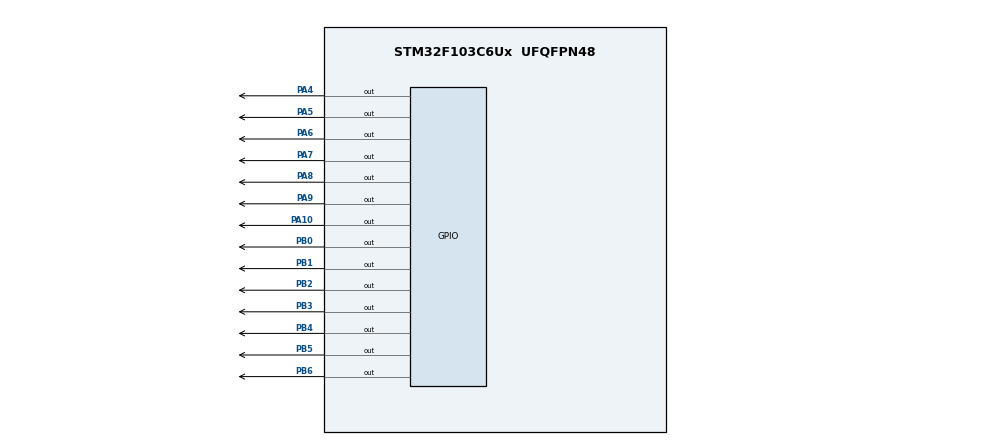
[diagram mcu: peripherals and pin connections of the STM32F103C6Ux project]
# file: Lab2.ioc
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Mcu.Family=STM32F1
Mcu.Name=STM32F103C6Ux
Mcu.Package=UFQFPN48
NVIC.PriorityGroup=NVIC_PRIORITYGROUP_4
NVIC.TIM2_IRQn=true\:0\:0\:false\:false\:true\:true\:true
PA10.Signal=GPIO_Output
PA4.Signal=GPIO_Output
PA5.Signal=GPIO_Output
PA6.Signal=GPIO_Output
PA7.Signal=GPIO_Output
PA8.Signal=GPIO_Output
PA9.Signal=GPIO_Output
PB0.Signal=GPIO_Output
PB1.Signal=GPIO_Output
PB2.Signal=GPIO_Output
PB3.Signal=GPIO_Output
PB4.Signal=GPIO_Output
PB5.Signal=GPIO_Output
PB6.Signal=GPIO_Output
ProjectManager.HeapSize=0x200
ProjectManager.StackSize=0x400
ProjectManager.TargetToolchain=STM32CubeIDE
RCC.APB1Freq_Value=8000000
RCC.APB2Freq_Value=8000000
TIM2.Period=9
TIM2.Prescaler=7999
VP_SYS_VS_ND.Mode=No_Debug
VP_TIM2_VS_ClockSourceINT.Mode=Internal
board=custom

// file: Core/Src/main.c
/* USER CODE BEGIN Header */
/**
  ******************************************************************************
  * @file           : main.c
  * @brief          : Main program body
  ******************************************************************************
  * @attention
  *
  * <h2><center>&copy; Copyright (c) 2021 STMicroelectronics.
  * All rights reserved.</center></h2>
  *
  * This software component is licensed by ST under BSD 3-Clause license,
  * the "License"; You may not use this file except in compliance with the
  * License. You may obtain a copy of the License at:
  *                        opensource.org/licenses/BSD-3-Clause
  *
  ******************************************************************************
  */
/* USER CODE END Header */
#include "main.h"

TIM_HandleTypeDef htim2;

void SystemClock_Config(void);
static void MX_TIM2_Init(void);
static void MX_GPIO_Init(void);

/* USER CODE BEGIN 0 */
int counter = 0;
int sw = 0;
const int MAX_LED = 4;
int index_led = 0;
int led_buffer [4] = {1 , 2 , 3 , 4};
int hour = 15 , minute = 8 , second = 50;

void update7SEG ( int index ) {
	switch ( index ) {
	case 0:
		HAL_GPIO_WritePin ( GPIOA , GPIO_PIN_7, SET ) ;
		HAL_GPIO_WritePin ( GPIOA , GPIO_PIN_8, SET ) ;
		HAL_GPIO_WritePin ( GPIOA , GPIO_PIN_9, SET ) ;
		display7SEG (led_buffer[index]);
		HAL_GPIO_WritePin ( GPIOA , GPIO_PIN_6, RESET ) ;
		break;
	case 1:
		HAL_GPIO_WritePin ( GPIOA , GPIO_PIN_6, SET ) ;
		HAL_GPIO_WritePin ( GPIOA , GPIO_PIN_8, SET ) ;
		HAL_GPIO_WritePin ( GPIOA , GPIO_PIN_9, SET ) ;
		display7SEG (led_buffer[index]);
		HAL_GPIO_WritePin ( GPIOA , GPIO_PIN_7, RESET ) ;
		break;
	case 2:
		HAL_GPIO_WritePin ( GPIOA , GPIO_PIN_6, SET ) ;
		HAL_GPIO_WritePin ( GPIOA , GPIO_PIN_7, SET ) ;
		HAL_GPIO_WritePin ( GPIOA , GPIO_PIN_9, SET ) ;
		display7SEG (led_buffer[index]);
		HAL_GPIO_WritePin ( GPIOA , GPIO_PIN_8, RESET ) ;
		break;
	case 3:
		HAL_GPIO_WritePin ( GPIOA , GPIO_PIN_6, SET ) ;
		HAL_GPIO_WritePin ( GPIOA , GPIO_PIN_7, SET ) ;
		HAL_GPIO_WritePin ( GPIOA , GPIO_PIN_8, SET ) ;
		display7SEG (led_buffer[index]);
		HAL_GPIO_WritePin ( GPIOA , GPIO_PIN_9, RESET ) ;
		break;
	default:
		break;
	}
}

void updateClockBuffer(){
	led_buffer[0] = hour/10;
	led_buffer[1] = hour%10;
	led_buffer[2] = minute/10;
	led_buffer[3] = minute%10;
}
uint8_t data[8] = {0xf7, 0xeb, 0xdd, 0xc1, 0xdd, 0xdd, 0xdd,0xff};
const int MAX_LED_MATRIX = 8;
int index_led_matrix = 0;
uint8_t matrix_buffer[8] = {0x01 , 0x02 , 0x03 , 0x04 , 0x05 , 0x06 , 0x07 , 0x08 };
void updateLEDMatrix (int index ) {
	switch ( index ) {
		case 0:
			HAL_GPIO_WritePin ( GPIOB , GPIO_PIN_8, SET ) ;
			HAL_GPIO_WritePin ( GPIOB , GPIO_PIN_9, SET ) ;
			HAL_GPIO_WritePin ( GPIOB , GPIO_PIN_10, SET ) ;
			HAL_GPIO_WritePin ( GPIOB , GPIO_PIN_11, SET ) ;
			HAL_GPIO_WritePin ( GPIOB , GPIO_PIN_12, SET ) ;
			HAL_GPIO_WritePin ( GPIOB , GPIO_PIN_13, SET ) ;
			HAL_GPIO_WritePin ( GPIOB , GPIO_PIN_14, SET ) ;
			HAL_GPIO_WritePin ( GPIOB , GPIO_PIN_15, SET ) ;
			displayMatrix(data[index]);
			data[index]=displayChange(data[index]);
			HAL_GPIO_WritePin ( GPIOB , GPIO_PIN_8, RESET ) ;
			break;
		case 1:
			HAL_GPIO_WritePin ( GPIOB , GPIO_PIN_8, SET ) ;
			HAL_GPIO_WritePin ( GPIOB , GPIO_PIN_9, SET ) ;
			HAL_GPIO_WritePin ( GPIOB , GPIO_PIN_10, SET ) ;
			HAL_GPIO_WritePin ( GPIOB , GPIO_PIN_11, SET ) ;
			HAL_GPIO_WritePin ( GPIOB , GPIO_PIN_12, SET ) ;
			HAL_GPIO_WritePin ( GPIOB , GPIO_PIN_13, SET ) ;
			HAL_GPIO_WritePin ( GPIOB , GPIO_PIN_14, SET ) ;
			HAL_GPIO_WritePin ( GPIOB , GPIO_PIN_15, SET ) ;
			displayMatrix(data[index]);
			data[index]=displayChange(data[index]);
			HAL_GPIO_WritePin ( GPIOB , GPIO_PIN_9, RESET ) ;
			break;
		case 2:
			HAL_GPIO_WritePin ( GPIOB , GPIO_PIN_8, SET ) ;
			HAL_GPIO_WritePin ( GPIOB , GPIO_PIN_9, SET ) ;
			HAL_GPIO_WritePin ( GPIOB , GPIO_PIN_10, SET ) ;
			HAL_GPIO_WritePin ( GPIOB , GPIO_PIN_11, SET ) ;
			HAL_GPIO_WritePin ( GPIOB , GPIO_PIN_12, SET ) ;
			HAL_GPIO_WritePin ( GPIOB , GPIO_PIN_13, SET ) ;
			HAL_GPIO_WritePin ( GPIOB , GPIO_PIN_14, SET ) ;
			HAL_GPIO_WritePin ( GPIOB , GPIO_PIN_15, SET ) ;
			displayMatrix(data[index]);
			data[index]=displayChange(data[index]);
			HAL_GPIO_WritePin ( GPIOB , GPIO_PIN_10, RESET ) ;
			break;
		case 3:
			HAL_GPIO_WritePin ( GPIOB , GPIO_PIN_8, SET ) ;
			HAL_GPIO_WritePin ( GPIOB , GPIO_PIN_9, SET ) ;
			HAL_GPIO_WritePin ( GPIOB , GPIO_PIN_10, SET ) ;
			HAL_GPIO_WritePin ( GPIOB , GPIO_PIN_11, SET ) ;
			HAL_GPIO_WritePin ( GPIOB , GPIO_PIN_12, SET ) ;
			HAL_GPIO_WritePin ( GPIOB , GPIO_PIN_13, SET ) ;
			HAL_GPIO_WritePin ( GPIOB , GPIO_PIN_14, SET ) ;
			HAL_GPIO_WritePin ( GPIOB , GPIO_PIN_15, SET ) ;
			displayMatrix(data[index]);
			data[index]=displayChange(data[index]);
			HAL_GPIO_WritePin ( GPIOB , GPIO_PIN_11, RESET ) ;
			break;
		case 4:
			HAL_GPIO_WritePin ( GPIOB , GPIO_PIN_8, SET ) ;
			HAL_GPIO_WritePin ( GPIOB , GPIO_PIN_9, SET ) ;
			HAL_GPIO_WritePin ( GPIOB , GPIO_PIN_10, SET ) ;
			HAL_GPIO_WritePin ( GPIOB , GPIO_PIN_11, SET ) ;
			HAL_GPIO_WritePin ( GPIOB , GPIO_PIN_12, SET ) ;
			HAL_GPIO_WritePin ( GPIOB , GPIO_PIN_13, SET ) ;
			HAL_GPIO_WritePin ( GPIOB , GPIO_PIN_14, SET ) ;
			HAL_GPIO_WritePin ( GPIOB , GPIO_PIN_15, SET ) ;
			displayMatrix(data[index]);
			data[index]=displayChange(data[index]);
			HAL_GPIO_WritePin ( GPIOB , GPIO_PIN_12, RESET ) ;
			break;
		case 5:
			HAL_GPIO_WritePin ( GPIOB , GPIO_PIN_8, SET ) ;
			HAL_GPIO_WritePin ( GPIOB , GPIO_PIN_9, SET ) ;
			HAL_GPIO_WritePin ( GPIOB , GPIO_PIN_10, SET ) ;
			HAL_GPIO_WritePin ( GPIOB , GPIO_PIN_11, SET ) ;
			HAL_GPIO_WritePin ( GPIOB , GPIO_PIN_12, SET ) ;
			HAL_GPIO_WritePin ( GPIOB , GPIO_PIN_13, SET ) ;
			HAL_GPIO_WritePin ( GPIOB , GPIO_PIN_14, SET ) ;
			HAL_GPIO_WritePin ( GPIOB , GPIO_PIN_15, SET ) ;
			displayMatrix(data[index]);
			data[index]=displayChange(data[index]);
			HAL_GPIO_WritePin ( GPIOB , GPIO_PIN_13, RESET ) ;
			break;
		case 6:
			HAL_GPIO_WritePin ( GPIOB , GPIO_PIN_8, SET ) ;
			HAL_GPIO_WritePin ( GPIOB , GPIO_PIN_9, SET ) ;
			HAL_GPIO_WritePin ( GPIOB , GPIO_PIN_10, SET ) ;
			HAL_GPIO_WritePin ( GPIOB , GPIO_PIN_11, SET ) ;
			HAL_GPIO_WritePin ( GPIOB , GPIO_PIN_12, SET ) ;
			HAL_GPIO_WritePin ( GPIOB , GPIO_PIN_13, SET ) ;
			HAL_GPIO_WritePin ( GPIOB , GPIO_PIN_14, SET ) ;
			HAL_GPIO_WritePin ( GPIOB , GPIO_PIN_15, SET ) ;
			displayMatrix(data[index]);
			data[index]=displayChange(data[index]);
			HAL_GPIO_WritePin ( GPIOB , GPIO_PIN_14, RESET ) ;
			break;
		case 7:
			HAL_GPIO_WritePin ( GPIOB , GPIO_PIN_8, SET ) ;
			HAL_GPIO_WritePin ( GPIOB , GPIO_PIN_9, SET ) ;
			HAL_GPIO_WritePin ( GPIOB , GPIO_PIN_10, SET ) ;
			HAL_GPIO_WritePin ( GPIOB , GPIO_PIN_11, SET ) ;
			HAL_GPIO_WritePin ( GPIOB , GPIO_PIN_12, SET ) ;
			HAL_GPIO_WritePin ( GPIOB , GPIO_PIN_13, SET ) ;
			HAL_GPIO_WritePin ( GPIOB , GPIO_PIN_14, SET ) ;
			HAL_GPIO_WritePin ( GPIOB , GPIO_PIN_15, SET ) ;
			displayMatrix(data[index]);
			data[index]=displayChange(data[index]);
			HAL_GPIO_WritePin ( GPIOB , GPIO_PIN_15, RESET ) ;
			break;

	}
}

void updateMatrixBuffer(){

	for(int i = 0; i<8; i++){
		matrix_buffer[i] = data[i];
	}
}

void blink_dot(){
	HAL_GPIO_TogglePin ( GPIOA , GPIO_PIN_4);
}

const int blink = 1000; //ms
const int switch_time = 250; //ms

const int TIMER_CYCLE = 10; //ms

int matrix_counter = 0;
int switch_counter = 0;
int timer0_counter = 0;
int matrix_flag = 0;
int timer0_flag = 0;
int switch_flag = 0;

void setMatrix0 ( int duration ) {
	matrix_counter = duration / TIMER_CYCLE ;
	matrix_flag = 0;
}

void setSwitch0 ( int duration ) {
	switch_counter = duration / TIMER_CYCLE ;
	switch_flag = 0;
}
void setTimer0 ( int duration ) {
	timer0_counter = duration / TIMER_CYCLE ;
	timer0_flag = 0;
}
void timer_run() {
	if( matrix_counter > 0) {
		matrix_counter--;
				if( matrix_counter == 0) matrix_flag = 1;
	}
	if( timer0_counter > 0) {
		timer0_counter--;
		if( timer0_counter == 0) timer0_flag = 1;
	}
	if( switch_counter > 0) {
		switch_counter--;
			if( switch_counter == 0) switch_flag = 1;
	}
}

void HAL_TIM_PeriodElapsedCallback ( TIM_HandleTypeDef * htim ){
	timer_run();
	//switch_counter--;
//	if(!switch_counter){
//		switch_counter = switch_time/TIMER_CYCLE;
//		update7SEG (index_led);
//		if(index_led==3) index_led=0;
//		else index_led++;
//	}
}
/* USER CODE END 0 */

int main(void)
{

  /* MCU Configuration--------------------------------------------------------*/

  /* Reset of all peripherals, Initializes the Flash interface and the Systick. */
  HAL_Init();

  /* Configure the system clock */
  SystemClock_Config();

  /* Initialize all configured peripherals */
  MX_TIM2_Init();
  MX_GPIO_Init();
  /* USER CODE BEGIN 2 */
  HAL_TIM_Base_Start_IT(&htim2);

  /* USER CODE END 2 */

  /* Infinite loop */
  /* USER CODE BEGIN WHILE */

  //if in line 1 of the code above is miss, what happens after that and why?
  //-- timer0_counter = 0 => timer0_flag never = 1 in timer_run() => LED unchange

  //if in line 1 of the code above is changed to setTimer0(1), what happens after that and why?
  //-- timer0_counter = 1/10 = 0 => LED unchange

  //if in line 1 of the code above is changed to setTimer0(10), what is changed compared to 2 first questions and why?
  //-- timer0_counter = 10/10 = 1 => After 10ms, LED change
  updateClockBuffer ();
  updateMatrixBuffer();
  setMatrix0 (25);
  setTimer0 (1000) ;
  setSwitch0 (250);
  while (1)
  {
    /* USER CODE END WHILE */

    /* USER CODE BEGIN 3 */
	  if(matrix_flag == 1){

		  	updateLEDMatrix (index_led_matrix);
	  		if(index_led_matrix==7) index_led_matrix=0;
	  		else index_led_matrix++;
	  		setMatrix0 (25);
	  	}
	  if(switch_flag == 1){

	  		update7SEG (index_led);
	  		if(index_led==3) index_led=0;
	  		else index_led++;
	  		setSwitch0 (250);
	  	}
	  if( timer0_flag == 1) {
		  blink_dot();

		  second++;
		 	  		if(second >= 60){
		 	  			second = 0;
		 	  			minute++;
		 	  		}
		 	  		if(minute >= 60){
		 	  			minute = 0;
		 	  			hour++;
		 	  		}
		 	  		if(hour >= 24){
		 	  			hour = 0;
		 	  		}
		 	  		updateClockBuffer ();

	   setTimer0 (1000) ;
	  }
  }
  /* USER CODE END 3 */
}

void SystemClock_Config(void)
{
  RCC_OscInitTypeDef RCC_OscInitStruct = {0};
  RCC_ClkInitTypeDef RCC_ClkInitStruct = {0};

  /** Initializes the RCC Oscillators according to the specified parameters
  * in the RCC_OscInitTypeDef structure.
  */
  RCC_OscInitStruct.OscillatorType = RCC_OSCILLATORTYPE_HSI;
  RCC_OscInitStruct.HSIState = RCC_HSI_ON;
  RCC_OscInitStruct.HSICalibrationValue = RCC_HSICALIBRATION_DEFAULT;
  RCC_OscInitStruct.PLL.PLLState = RCC_PLL_NONE;
  if (HAL_RCC_OscConfig(&RCC_OscInitStruct) != HAL_OK)
  {
    Error_Handler();
  }
  /** Initializes the CPU, AHB and APB buses clocks
  */
  RCC_ClkInitStruct.ClockType = RCC_CLOCKTYPE_HCLK|RCC_CLOCKTYPE_SYSCLK
                              |RCC_CLOCKTYPE_PCLK1|RCC_CLOCKTYPE_PCLK2;
  RCC_ClkInitStruct.SYSCLKSource = RCC_SYSCLKSOURCE_HSI;
  RCC_ClkInitStruct.AHBCLKDivider = RCC_SYSCLK_DIV1;
  RCC_ClkInitStruct.APB1CLKDivider = RCC_HCLK_DIV1;
  RCC_ClkInitStruct.APB2CLKDivider = RCC_HCLK_DIV1;

  if (HAL_RCC_ClockConfig(&RCC_ClkInitStruct, FLASH_LATENCY_0) != HAL_OK)
  {
    Error_Handler();
  }
}

static void MX_TIM2_Init(void)
{

  TIM_ClockConfigTypeDef sClockSourceConfig = {0};
  TIM_MasterConfigTypeDef sMasterConfig = {0};

  htim2.Instance = TIM2;
  htim2.Init.Prescaler = 7999;
  htim2.Init.CounterMode = TIM_COUNTERMODE_UP;
  htim2.Init.Period = 9;
  htim2.Init.ClockDivision = TIM_CLOCKDIVISION_DIV1;
  htim2.Init.AutoReloadPreload = TIM_AUTORELOAD_PRELOAD_DISABLE;
  if (HAL_TIM_Base_Init(&htim2) != HAL_OK)
  {
    Error_Handler();
  }
  sClockSourceConfig.ClockSource = TIM_CLOCKSOURCE_INTERNAL;
  if (HAL_TIM_ConfigClockSource(&htim2, &sClockSourceConfig) != HAL_OK)
  {
    Error_Handler();
  }
  sMasterConfig.MasterOutputTrigger = TIM_TRGO_RESET;
  sMasterConfig.MasterSlaveMode = TIM_MASTERSLAVEMODE_DISABLE;
  if (HAL_TIMEx_MasterConfigSynchronization(&htim2, &sMasterConfig) != HAL_OK)
  {
    Error_Handler();
  }

}

static void MX_GPIO_Init(void)
{
  GPIO_InitTypeDef GPIO_InitStruct = {0};

  /* GPIO Ports Clock Enable */
  __HAL_RCC_GPIOA_CLK_ENABLE();
  __HAL_RCC_GPIOB_CLK_ENABLE();

  /*Configure GPIO pin Output Level */
  HAL_GPIO_WritePin(GPIOA, GPIO_PIN_1|GPIO_PIN_2|GPIO_PIN_3|GPIO_PIN_4
                          |GPIO_PIN_5|GPIO_PIN_6|GPIO_PIN_7|GPIO_PIN_8
                          |GPIO_PIN_9|GPIO_PIN_10|GPIO_PIN_11|GPIO_PIN_12
                          |GPIO_PIN_13|GPIO_PIN_14|GPIO_PIN_15, GPIO_PIN_RESET);

  /*Configure GPIO pin Output Level */
  HAL_GPIO_WritePin(GPIOB, GPIO_PIN_0|GPIO_PIN_1|GPIO_PIN_2|GPIO_PIN_10
                          |GPIO_PIN_11|GPIO_PIN_12|GPIO_PIN_13|GPIO_PIN_14
                          |GPIO_PIN_15|GPIO_PIN_3|GPIO_PIN_4|GPIO_PIN_5
                          |GPIO_PIN_6|GPIO_PIN_7|GPIO_PIN_8|GPIO_PIN_9, GPIO_PIN_RESET);

  /*Configure GPIO pins : PA1 PA2 PA3 PA4
                           PA5 PA6 PA7 PA8
                           PA9 PA10 PA11 PA12
                           PA13 PA14 PA15 */
  GPIO_InitStruct.Pin = GPIO_PIN_1|GPIO_PIN_2|GPIO_PIN_3|GPIO_PIN_4
                          |GPIO_PIN_5|GPIO_PIN_6|GPIO_PIN_7|GPIO_PIN_8
                          |GPIO_PIN_9|GPIO_PIN_10|GPIO_PIN_11|GPIO_PIN_12
                          |GPIO_PIN_13|GPIO_PIN_14|GPIO_PIN_15;
  GPIO_InitStruct.Mode = GPIO_MODE_OUTPUT_PP;
  GPIO_InitStruct.Pull = GPIO_NOPULL;
  GPIO_InitStruct.Speed = GPIO_SPEED_FREQ_LOW;
  HAL_GPIO_Init(GPIOA, &GPIO_InitStruct);

  /*Configure GPIO pins : PB0 PB1 PB2 PB10
                           PB11 PB12 PB13 PB14
                           PB15 PB3 PB4 PB5
                           PB6 PB7 PB8 PB9 */
  GPIO_InitStruct.Pin = GPIO_PIN_0|GPIO_PIN_1|GPIO_PIN_2|GPIO_PIN_10
                          |GPIO_PIN_11|GPIO_PIN_12|GPIO_PIN_13|GPIO_PIN_14
                          |GPIO_PIN_15|GPIO_PIN_3|GPIO_PIN_4|GPIO_PIN_5
                          |GPIO_PIN_6|GPIO_PIN_7|GPIO_PIN_8|GPIO_PIN_9;
  GPIO_InitStruct.Mode = GPIO_MODE_OUTPUT_PP;
  GPIO_InitStruct.Pull = GPIO_NOPULL;
  GPIO_InitStruct.Speed = GPIO_SPEED_FREQ_LOW;
  HAL_GPIO_Init(GPIOB, &GPIO_InitStruct);

}

void Error_Handler(void)
{
  __disable_irq();
  while (1)
  {
  }
}

/************************ (C) COPYRIGHT STMicroelectronics *****END OF FILE****/
